One B-rep face of a CAD part: STEP entity #2333.
In plain terms, the planar face has unit normal (0, 0, 1).
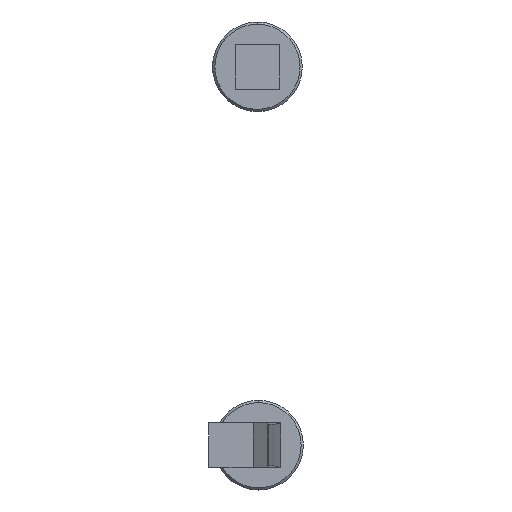
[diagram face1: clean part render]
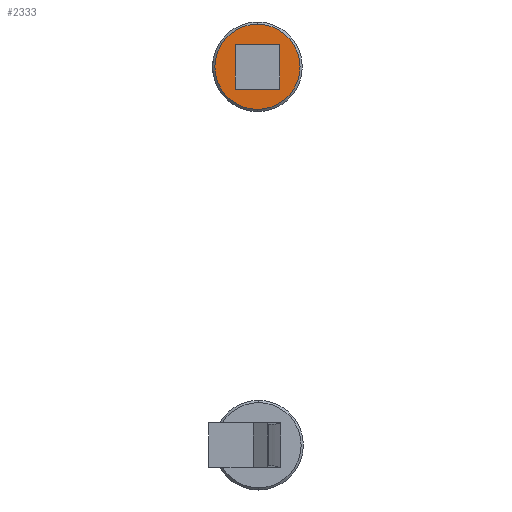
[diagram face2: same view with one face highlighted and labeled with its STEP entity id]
Its self-contained STEP definition (entity closure, numbers rounded to 3 decimals):
#7 = EDGE_CURVE ( 'NONE', #1085, #1118, #1853, .T. ) ;
#9 = EDGE_CURVE ( 'NONE', #1077, #1087, #2244, .T. ) ;
#482 = CARTESIAN_POINT ( 'NONE',  ( 0., 2., 6. ) ) ;
#492 = LINE ( 'NONE', #504, #826 ) ;
#496 = DIRECTION ( 'NONE',  ( 1., 0., 0. ) ) ;
#504 = CARTESIAN_POINT ( 'NONE',  ( 2., 0., 6. ) ) ;
#505 = DIRECTION ( 'NONE',  ( 0., -1., 0. ) ) ;
#510 = LINE ( 'NONE', #482, #845 ) ;
#577 = CARTESIAN_POINT ( 'NONE',  ( 0., 0., 6. ) ) ;
#581 = DIRECTION ( 'NONE',  ( -1., 0., 0. ) ) ;
#613 = DIRECTION ( 'NONE',  ( 0., 0., -1. ) ) ;
#714 = DIRECTION ( 'NONE',  ( 0., 1., 0. ) ) ;
#725 = CARTESIAN_POINT ( 'NONE',  ( -2., 0., 6. ) ) ;
#728 = LINE ( 'NONE', #725, #1734 ) ;
#826 = VECTOR ( 'NONE', #505, 1000. ) ;
#845 = VECTOR ( 'NONE', #496, 1000. ) ;
#850 = AXIS2_PLACEMENT_3D ( 'NONE', #577, #613, #581 ) ;
#866 = CIRCLE ( 'NONE', #850, 3.8 ) ;
#951 = EDGE_LOOP ( 'NONE', ( #1983, #2092, #2039, #1060 ) ) ;
#962 = EDGE_LOOP ( 'NONE', ( #1064, #1057 ) ) ;
#1057 = ORIENTED_EDGE ( 'NONE', *, *, #9, .F. ) ;
#1060 = ORIENTED_EDGE ( 'NONE', *, *, #2493, .T. ) ;
#1064 = ORIENTED_EDGE ( 'NONE', *, *, #2448, .F. ) ;
#1077 = VERTEX_POINT ( 'NONE', #2519 ) ;
#1085 = VERTEX_POINT ( 'NONE', #2521 ) ;
#1087 = VERTEX_POINT ( 'NONE', #2527 ) ;
#1097 = VERTEX_POINT ( 'NONE', #2537 ) ;
#1109 = VERTEX_POINT ( 'NONE', #2564 ) ;
#1118 = VERTEX_POINT ( 'NONE', #2571 ) ;
#1252 = FACE_BOUND ( 'NONE', #951, .T. ) ;
#1253 = PLANE ( 'NONE',  #2142 ) ;
#1260 = DIRECTION ( 'NONE',  ( 1., 0., 0. ) ) ;
#1269 = FACE_OUTER_BOUND ( 'NONE', #962, .T. ) ;
#1272 = DIRECTION ( 'NONE',  ( 0., 0., 1. ) ) ;
#1273 = CARTESIAN_POINT ( 'NONE',  ( 0., 0., 6. ) ) ;
#1734 = VECTOR ( 'NONE', #714, 1000. ) ;
#1798 = CARTESIAN_POINT ( 'NONE',  ( 0., -2., 6. ) ) ;
#1802 = DIRECTION ( 'NONE',  ( -1., 0., 0. ) ) ;
#1853 = LINE ( 'NONE', #1798, #2221 ) ;
#1983 = ORIENTED_EDGE ( 'NONE', *, *, #2419, .T. ) ;
#2039 = ORIENTED_EDGE ( 'NONE', *, *, #7, .T. ) ;
#2054 = CARTESIAN_POINT ( 'NONE',  ( 0., 0., 6. ) ) ;
#2057 = DIRECTION ( 'NONE',  ( 0., 0., -1. ) ) ;
#2092 = ORIENTED_EDGE ( 'NONE', *, *, #2427, .T. ) ;
#2095 = DIRECTION ( 'NONE',  ( -1., 0., 0. ) ) ;
#2142 = AXIS2_PLACEMENT_3D ( 'NONE', #1273, #1272, #1260 ) ;
#2221 = VECTOR ( 'NONE', #1802, 1000. ) ;
#2233 = AXIS2_PLACEMENT_3D ( 'NONE', #2054, #2057, #2095 ) ;
#2244 = CIRCLE ( 'NONE', #2233, 3.8 ) ;
#2333 = ADVANCED_FACE ( 'NONE', ( #1252, #1269 ), #1253, .T. ) ;
#2419 = EDGE_CURVE ( 'NONE', #1109, #1097, #510, .T. ) ;
#2427 = EDGE_CURVE ( 'NONE', #1097, #1085, #492, .T. ) ;
#2448 = EDGE_CURVE ( 'NONE', #1087, #1077, #866, .T. ) ;
#2493 = EDGE_CURVE ( 'NONE', #1118, #1109, #728, .T. ) ;
#2519 = CARTESIAN_POINT ( 'NONE',  ( 3.8, 0., 6. ) ) ;
#2521 = CARTESIAN_POINT ( 'NONE',  ( 2., -2., 6. ) ) ;
#2527 = CARTESIAN_POINT ( 'NONE',  ( -3.8, 0., 6. ) ) ;
#2537 = CARTESIAN_POINT ( 'NONE',  ( 2., 2., 6. ) ) ;
#2564 = CARTESIAN_POINT ( 'NONE',  ( -2., 2., 6. ) ) ;
#2571 = CARTESIAN_POINT ( 'NONE',  ( -2., -2., 6. ) ) ;
